VERSION 5.7 ;
  NOWIREEXTENSIONATPIN ON ;
  DIVIDERCHAR "/" ;
  BUSBITCHARS "[]" ;
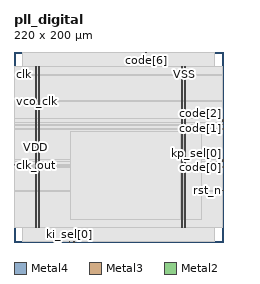
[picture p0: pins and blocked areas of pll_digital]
MACRO pll_digital
  CLASS BLOCK ;
  FOREIGN pll_digital ;
  ORIGIN 0.000 0.000 ;
  SIZE 220.000 BY 200.000 ;
  PIN VDD
    DIRECTION INOUT ;
    USE POWER ;
    PORT
      LAYER Metal4 ;
        RECT 22.240 15.380 23.840 184.540 ;
    END
    PORT
      LAYER Metal4 ;
        RECT 175.840 15.380 177.440 184.540 ;
    END
  END VDD
  PIN VSS
    DIRECTION INOUT ;
    USE GROUND ;
    PORT
      LAYER Metal4 ;
        RECT 25.540 15.380 27.140 184.540 ;
    END
    PORT
      LAYER Metal4 ;
        RECT 179.140 15.380 180.740 184.540 ;
    END
  END VSS
  PIN clk
    DIRECTION INPUT ;
    USE SIGNAL ;
    ANTENNAGATEAREA 4.738000 ;
    PORT
      LAYER Metal3 ;
        RECT 0.000 175.840 0.560 176.400 ;
    END
  END clk
  PIN clk_out
    DIRECTION OUTPUT ;
    USE SIGNAL ;
    ANTENNADIFFAREA 0.897600 ;
    PORT
      LAYER Metal3 ;
        RECT 0.000 80.640 0.560 81.200 ;
    END
  END clk_out
  PIN code[0]
    DIRECTION OUTPUT ;
    USE SIGNAL ;
    ANTENNADIFFAREA 0.897600 ;
    PORT
      LAYER Metal3 ;
        RECT 219.440 78.400 220.000 78.960 ;
    END
  END code[0]
  PIN code[1]
    DIRECTION OUTPUT ;
    USE SIGNAL ;
    ANTENNADIFFAREA 0.897600 ;
    PORT
      LAYER Metal3 ;
        RECT 219.440 118.720 220.000 119.280 ;
    END
  END code[1]
  PIN code[2]
    DIRECTION OUTPUT ;
    USE SIGNAL ;
    ANTENNADIFFAREA 0.897600 ;
    PORT
      LAYER Metal3 ;
        RECT 219.440 126.560 220.000 127.120 ;
    END
  END code[2]
  PIN code[3]
    DIRECTION OUTPUT ;
    USE SIGNAL ;
    ANTENNADIFFAREA 0.897600 ;
    PORT
      LAYER Metal3 ;
        RECT 219.440 123.200 220.000 123.760 ;
    END
  END code[3]
  PIN code[4]
    DIRECTION OUTPUT ;
    USE SIGNAL ;
    ANTENNADIFFAREA 0.897600 ;
    PORT
      LAYER Metal3 ;
        RECT 219.440 127.680 220.000 128.240 ;
    END
  END code[4]
  PIN code[5]
    DIRECTION OUTPUT ;
    USE SIGNAL ;
    ANTENNADIFFAREA 0.897600 ;
    PORT
      LAYER Metal3 ;
        RECT 219.440 128.800 220.000 129.360 ;
    END
  END code[5]
  PIN code[6]
    DIRECTION OUTPUT ;
    USE SIGNAL ;
    ANTENNADIFFAREA 0.897600 ;
    PORT
      LAYER Metal2 ;
        RECT 138.880 199.440 139.440 200.000 ;
    END
  END code[6]
  PIN ki_sel[0]
    DIRECTION INPUT ;
    USE SIGNAL ;
    ANTENNAGATEAREA 0.498500 ;
    PORT
      LAYER Metal2 ;
        RECT 58.240 0.000 58.800 0.560 ;
    END
  END ki_sel[0]
  PIN ki_sel[1]
    DIRECTION INPUT ;
    USE SIGNAL ;
    ANTENNAGATEAREA 0.498500 ;
    PORT
      LAYER Metal2 ;
        RECT 62.720 0.000 63.280 0.560 ;
    END
  END ki_sel[1]
  PIN kp_sel[0]
    DIRECTION INPUT ;
    USE SIGNAL ;
    ANTENNAGATEAREA 0.498500 ;
    PORT
      LAYER Metal3 ;
        RECT 219.440 85.120 220.000 85.680 ;
    END
  END kp_sel[0]
  PIN kp_sel[1]
    DIRECTION INPUT ;
    USE SIGNAL ;
    ANTENNAGATEAREA 0.498500 ;
    PORT
      LAYER Metal3 ;
        RECT 219.440 86.240 220.000 86.800 ;
    END
  END kp_sel[1]
  PIN lock
    DIRECTION OUTPUT ;
    USE SIGNAL ;
    ANTENNADIFFAREA 0.897600 ;
    PORT
      LAYER Metal2 ;
        RECT 162.400 199.440 162.960 200.000 ;
    END
  END lock
  PIN rst_n
    DIRECTION INPUT ;
    USE SIGNAL ;
    ANTENNAGATEAREA 1.102000 ;
    PORT
      LAYER Metal3 ;
        RECT 219.440 53.760 220.000 54.320 ;
    END
  END rst_n
  PIN vco_clk
    DIRECTION INPUT ;
    USE SIGNAL ;
    ANTENNAGATEAREA 4.738000 ;
    PORT
      LAYER Metal3 ;
        RECT 0.000 147.840 0.560 148.400 ;
    END
  END vco_clk
  OBS
      LAYER Nwell ;
        RECT 6.290 15.250 213.230 184.670 ;
      LAYER Metal1 ;
        RECT 6.720 15.380 212.800 184.540 ;
      LAYER Metal2 ;
        RECT 8.540 199.140 138.580 199.780 ;
        RECT 139.740 199.140 162.100 199.780 ;
        RECT 163.260 199.140 211.540 199.780 ;
        RECT 8.540 0.860 211.540 199.140 ;
        RECT 8.540 0.560 57.940 0.860 ;
        RECT 59.100 0.560 62.420 0.860 ;
        RECT 63.580 0.560 211.540 0.860 ;
      LAYER Metal3 ;
        RECT 0.560 176.700 219.440 184.380 ;
        RECT 0.860 175.540 219.440 176.700 ;
        RECT 0.560 148.700 219.440 175.540 ;
        RECT 0.860 147.540 219.440 148.700 ;
        RECT 0.560 129.660 219.440 147.540 ;
        RECT 0.560 126.260 219.140 129.660 ;
        RECT 0.560 124.060 219.440 126.260 ;
        RECT 0.560 122.900 219.140 124.060 ;
        RECT 0.560 119.580 219.440 122.900 ;
        RECT 0.560 118.420 219.140 119.580 ;
        RECT 0.560 87.100 219.440 118.420 ;
        RECT 0.560 84.820 219.140 87.100 ;
        RECT 0.560 81.500 219.440 84.820 ;
        RECT 0.860 80.340 219.440 81.500 ;
        RECT 0.560 79.260 219.440 80.340 ;
        RECT 0.560 78.100 219.140 79.260 ;
        RECT 0.560 54.620 219.440 78.100 ;
        RECT 0.560 53.460 219.140 54.620 ;
        RECT 0.560 15.540 219.440 53.460 ;
      LAYER Metal4 ;
        RECT 59.500 23.610 175.540 115.830 ;
        RECT 177.740 23.610 178.840 115.830 ;
        RECT 181.040 23.610 197.540 115.830 ;
  END
END pll_digital
END LIBRARY

